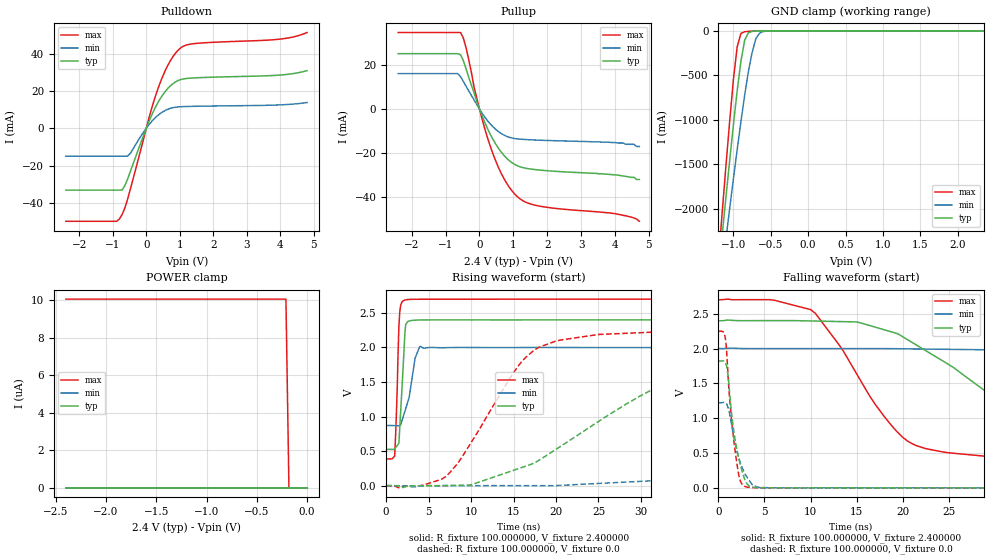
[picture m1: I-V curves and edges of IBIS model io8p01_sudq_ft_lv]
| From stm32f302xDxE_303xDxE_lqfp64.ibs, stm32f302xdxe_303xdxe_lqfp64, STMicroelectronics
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|   Model io8p01_sudq_ft_lv
[Model]  io8p01_sudq_ft_lv
Model_type I/O
Polarity   Non-Inverting
Enable   Active-Low
Vinl =   0.720000V
Vinh =   1.680000V
Vmeas =  1.200000V
Cref =   50.000000pF
Rref =   100.000000M
Vref =   0.0V
C_comp   1.970100pF   1.887900pF   2.069400pF
[Temperature Range]   25.000000   0.125000k   -40.000000
[Pullup Reference]   2.400000V   2.000000V   2.700000V
[Pulldown Reference]   0.0V   0.0V   0.0V
[POWER Clamp Reference]   2.400000V   2.000000V   2.700000V
[GND Clamp Reference]   0.0V   0.0V   0.0V
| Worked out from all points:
|   slope of the pulldown table from 0 to 0.36 V, typ, clamps not added: 25.5 ohm
|   slope of the pullup table from 0 to 0.36 V, typ, clamps not added: 28.4 ohm
|   GND clamp passes 1 mA (typ) near -0.64 V on its own axis
|   rising waveform, R_fixture 100.000000, V_fixture 2.400000: 20-80 % time 499ps typ, 1.06ns min, 336ps max; typ from 0.525 V to 2.4 V
|   rising waveform, R_fixture 100.000000, V_fixture 0.0: 20-80 % time 14.5ns typ, 43.7ns min, 6.87ns max; typ from 0 V to 1.82 V
|   falling waveform, R_fixture 100.000000, V_fixture 2.400000: 20-80 % time 13ns typ, 32.3ns min, 7.05ns max; typ from 2.4 V to 0.525 V
|   falling waveform, R_fixture 100.000000, V_fixture 0.0: 20-80 % time 1.16ns typ, 1.39ns min, 931ps max; typ from 1.82 V to 0 V
[Pulldown]
|Voltage   I(typ)   I(min)   I(max)
-2.4V     -33.16mA   -14.98mA   -49.86mA
-880mV    -33.16mA   -14.98mA   -49.86mA
-800mV    -33.16mA   -14.98mA   -48.55mA
-640mV    -30.75mA   -14.98mA   -42.76mA
-480mV    -23.43mA   -13.57mA   -32.92mA
80mV      3.651mA    1.905mA    5.506mA
400mV     15.37mA    7.665mA    23.73mA
720mV     22.75mA    10.69mA    36.23mA
1.04V     26.18mA    11.57mA    43.27mA
1.52V     27.09mA    11.81mA    45.55mA
4V        28.55mA    12.55mA    47.81mA
4.8V      30.9mA     13.81mA    51.31mA
[Pullup]
|Voltage   I(typ)   I(min)   I(max)
-2.4V     25.21mA    16.13mA    34.79mA
-640mV    25.21mA    16.13mA    34.79mA
-560mV    24.72mA    14.75mA    34.79mA
-400mV    18.51mA    10.48mA    28.09mA
-160mV    7.322mA    4.15mA     10.02mA
80mV      -3.229mA   -1.94mA    -4.736mA
400mV     -13.82mA   -8.081mA   -20.45mA
800mV     -22.31mA   -12.38mA   -33.66mA
1.2V      -26.24mA   -13.65mA   -40.83mA
1.76V     -27.69mA   -14.12mA   -44.07mA
4V        -29.9mA    -15.2mA    -47.5mA
4.72V     -32mA      -17mA      -51mA
[GND_clamp]
|Voltage   I(typ)   I(min)   I(max)
-2.4V     -9.788A    -9.782A    -9.734A
-1.2V     -2.718A    -3.02A     -2.568A
-1.15V    -2.29A     -2.675A    -2.036A
-1.1V     -1.868A    -2.333A    -1.515A
-1.05V    -1.454A    -1.995A    -1.012A
-950mV    -674.5mA   -1.337A    -180.5mA
-900mV    -345.2mA   -1.023A    -29.72mA
-850mV    -106.4mA   -726mA     -10.13mA
-750mV    -6.396mA   -244mA     -4.026mA
-700mV    -2.558mA   -88.61mA   -2.329mA
-600mV    -416uA     -7.739mA   -368uA
2.35V     0A         0A         0A
[POWER_clamp]
|Voltage   I(typ)   I(min)   I(max)
-2.4V     0A         0A         10.06uA
-210mV    0A         0A         10.06uA
-180mV    0A         0A         0A
0V        0A         0A         0A
[Ramp]
| variable   typ   min   max
dV/dt_r  1.09308/14.53591n   0.73368/43.60005n   1.34946/6.86189n
dV/dt_f  1.12469/12.94342n   0.67781/32.23620n   1.38756/7.04174n
R_load = 100.000000
[Rising Waveform]
R_fixture= 100.000000
V_fixture= 2.400000
V_fixture_min= 2.000000
V_fixture_max= 2.700000
|time   V(typ)   V(min)   V(max)
0s        525.2mV    870.3mV    387.4mV
1.001ns   533.4mV    868.6mV    427.9mV
1.301ns   580.2mV    867mV      1.396V
1.502ns   618.9mV    866.4mV    2.308V
1.702ns   1.058V     877.1mV    2.607V
2.202ns   2.2V       1.075V     2.686V
2.703ns   2.383V     1.274V     2.696V
3.403ns   2.395V     1.844V     2.698V
4.004ns   2.398V     2.016V     2.698V
49.85ns   2.4V       2V         2.7V
[Rising Waveform]
R_fixture= 100.000000
V_fixture= 0.0
V_fixture_min= 0.0
V_fixture_max= 0.0
|time   V(typ)   V(min)   V(max)
0s        1.81nV     16.19nV    1.388nV
7.007ns   1.867mV    817.4uV    130.2mV
16.52ns   286.2mV    456uV      1.866V
20.02ns   528mV      1.164mV    2.095V
25.03ns   931.2mV    32.13mV    2.189V
37.04ns   1.629V     132.6mV    2.24V
54.55ns   1.791V     444.2mV    2.251V
84.08ns   1.821V     947.3mV    2.249V
106.1ns   1.822V     1.128V     2.249V
249.2ns   1.822V     1.223V     2.249V
[Falling Waveform]
R_fixture= 100.000000
V_fixture= 2.400000
V_fixture_min= 2.000000
V_fixture_max= 2.700000
|time   V(typ)   V(min)   V(max)
0s        2.4V       2V         2.7V
10.01ns   2.397V     2V         2.56V
15.02ns   2.383V     2V         1.637V
20.02ns   2.171V     1.997V     726.6mV
29.03ns   1.387V     1.983V     453.9mV
37.04ns   789.8mV    1.94V      415.8mV
52.55ns   592.4mV    1.669V     394.5mV
72.57ns   546.2mV    1.209V     388.6mV
99.1ns    528mV      969.1mV    387.4mV
249.2ns   525.2mV    870.3mV    387.4mV
[Falling Waveform]
R_fixture= 100.000000
V_fixture= 0.0
V_fixture_min= 0.0
V_fixture_max= 0.0
|time   V(typ)   V(min)   V(max)
0s        1.822V     1.223V     2.249V
700.7ps   1.802V     1.223V     2.18V
800.8ps   1.785V     1.216V     2.097V
1.001ns   1.655V     1.166V     1.704V
1.201ns   1.378V     1.071V     1.289V
1.902ns   616.6mV    591.6mV    436.6mV
2.302ns   369.3mV    388.2mV    131.7mV
2.903ns   108.1mV    191.2mV    18.1mV
4.705ns   2.197mV    4.103mV    1.139mV
49.85ns   1.81nV     16.19nV    1.388nV
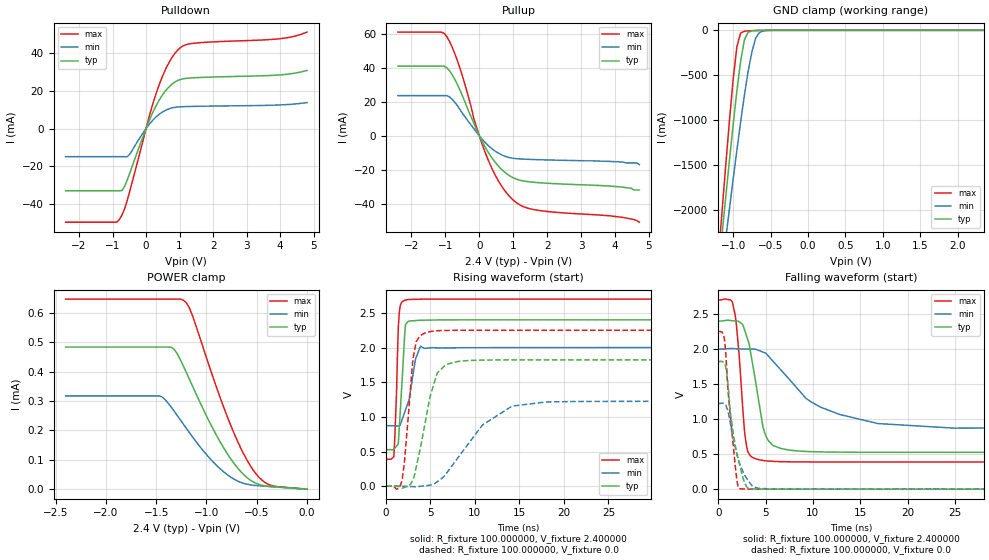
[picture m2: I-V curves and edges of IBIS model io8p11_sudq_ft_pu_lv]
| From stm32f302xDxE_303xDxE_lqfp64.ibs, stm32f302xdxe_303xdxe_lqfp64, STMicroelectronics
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|   Model io8p11_sudq_ft_pu_lv
[Model]  io8p11_sudq_ft_pu_lv
Model_type I/O
Polarity   Non-Inverting
Enable   Active-Low
Vinl =   0.720000V
Vinh =   1.680000V
Vmeas =  1.200000V
Cref =   50.000000pF
Rref =   100.000000M
Vref =   0.0V
C_comp   1.970100pF   1.887900pF   2.069400pF
[Temperature Range]   25.000000   0.125000k   -40.000000
[Pullup Reference]   2.400000V   2.000000V   2.700000V
[Pulldown Reference]   0.0V   0.0V   0.0V
[POWER Clamp Reference]   2.400000V   2.000000V   2.700000V
[GND Clamp Reference]   0.0V   0.0V   0.0V
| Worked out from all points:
|   slope of the pulldown table from 0 to 0.36 V, typ, clamps not added: 25.5 ohm
|   slope of the pullup table from 0 to 0.36 V, typ, clamps not added: 28.4 ohm
|   GND clamp passes 1 mA (typ) near -0.64 V on its own axis
|   rising waveform, R_fixture 100.000000, V_fixture 2.400000: 20-80 % time 508ps typ, 1.05ns min, 337ps max; typ from 0.527 V to 2.4 V
|   rising waveform, R_fixture 100.000000, V_fixture 0.0: 20-80 % time 1.8ns typ, 4.87ns min, 863ps max; typ from 0.001 V to 1.82 V
|   falling waveform, R_fixture 100.000000, V_fixture 2.400000: 20-80 % time 1.39ns typ, 6.08ns min, 775ps max; typ from 2.4 V to 0.527 V
|   falling waveform, R_fixture 100.000000, V_fixture 0.0: 20-80 % time 1.17ns typ, 1.4ns min, 853ps max; typ from 1.82 V to 0.001 V
[Pulldown]
|Voltage   I(typ)   I(min)   I(max)
-2.4V     -33.16mA   -14.98mA   -49.86mA
-880mV    -33.16mA   -14.98mA   -49.86mA
-800mV    -33.16mA   -14.98mA   -48.55mA
-640mV    -30.75mA   -14.98mA   -42.77mA
-480mV    -23.43mA   -13.57mA   -32.92mA
80mV      3.651mA    1.905mA    5.506mA
400mV     15.37mA    7.665mA    23.73mA
720mV     22.75mA    10.69mA    36.23mA
1.04V     26.18mA    11.57mA    43.27mA
1.52V     27.09mA    11.81mA    45.55mA
4V        28.55mA    12.55mA    47.81mA
4.8V      30.9mA     13.81mA    51.31mA
[Pullup]
|Voltage   I(typ)   I(min)   I(max)
-2.4V     41.12mA    23.71mA    61.21mA
-1.12V    41.12mA    23.71mA    61.21mA
-960mV    40.18mA    23.71mA    58.56mA
-800mV    36.01mA    21.55mA    52.29mA
-560mV    26.54mA    15.18mA    39.21mA
-160mV    7.421mA    4.162mA    10.02mA
240mV     -8.977mA   -5.327mA   -13.21mA
640mV     -19.51mA   -11.09mA   -29.16mA
1.04V     -25.15mA   -13.38mA   -38.61mA
1.68V     -27.56mA   -14.07mA   -43.82mA
3.84V     -29.6mA    -15.1mA    -47.2mA
4.72V     -32mA      -17mA      -51mA
[GND_clamp]
|Voltage   I(typ)   I(min)   I(max)
-2.4V     -9.788A    -9.782A    -9.734A
-1.2V     -2.718A    -3.02A     -2.568A
-1.15V    -2.29A     -2.675A    -2.036A
-1.1V     -1.868A    -2.333A    -1.515A
-1.05V    -1.454A    -1.995A    -1.012A
-950mV    -674.5mA   -1.337A    -180.5mA
-900mV    -345.2mA   -1.023A    -29.72mA
-850mV    -106.4mA   -726mA     -10.13mA
-750mV    -6.396mA   -244mA     -4.026mA
-700mV    -2.558mA   -88.61mA   -2.329mA
-600mV    -416uA     -7.739mA   -368uA
2.35V     0A         0A         0A
[POWER_clamp]
|Voltage   I(typ)   I(min)   I(max)
-2.4V     483.8uA    317.4uA    647uA
-1.47V    483.8uA    317.4uA    647uA
-1.32V    475.6uA    265.2uA    647uA
-1.23V    419.7uA    221.6uA    643.3uA
-1.17V    374.8uA    192.7uA    617.6uA
-1.14V    352.1uA    178.7uA    591.9uA
-840mV    147uA      62.15uA    289.6uA
-690mV    72.24uA    27.76uA    162.7uA
-540mV    25.74uA    13.55uA    67.63uA
-450mV    13.38uA    10.75uA    31.36uA
-360mV    9.231uA    8.535uA    12.97uA
0V        0A         0A         0A
[Ramp]
| variable   typ   min   max
dV/dt_r  1.09269/1.79328n   0.73359/4.86832n   1.34926/0.85997n
dV/dt_f  1.12411/1.38607n   0.67669/6.07307n   1.38681/0.77427n
R_load = 100.000000
[Rising Waveform]
R_fixture= 100.000000
V_fixture= 2.400000
V_fixture_min= 2.000000
V_fixture_max= 2.700000
|time   V(typ)   V(min)   V(max)
0s        526.5mV    872.5mV    388.6mV
900.9ps   534.2mV    870.9mV    425.1mV
1.201ns   577.4mV    869.6mV    1.365V
1.401ns   613.7mV    869.2mV    2.295V
1.602ns   1.046V     879.2mV    2.598V
2.202ns   2.333V     1.099V     2.686V
2.603ns   2.381V     1.245V     2.693V
3.303ns   2.389V     1.817V     2.697V
3.904ns   2.394V     2.019V     2.698V
49.85ns   2.4V       2V         2.7V
[Rising Waveform]
R_fixture= 100.000000
V_fixture= 0.0
V_fixture_min= 0.0
V_fixture_max= 0.0
|time   V(typ)   V(min)   V(max)
0s        1.022mV    1.341mV    911uV
1.802ns   -26.21mV   109.9uV    74.5mV
3.103ns   116.7mV    -6.8mV     1.877V
3.403ns   271.6mV    -8.185mV   2.086V
4.505ns   979.1mV    4.99mV     2.215V
5.706ns   1.605V     58.19mV    2.241V
6.707ns   1.752V     167.1mV    2.247V
10.81ns   1.819V     875.7mV    2.25V
14.21ns   1.822V     1.156V     2.25V
49.85ns   1.822V     1.224V     2.25V
[Falling Waveform]
R_fixture= 100.000000
V_fixture= 2.400000
V_fixture_min= 2.000000
V_fixture_max= 2.700000
|time   V(typ)   V(min)   V(max)
0s        2.4V       2V         2.7V
1.502ns   2.403V     2.008V     2.671V
1.902ns   2.401V     2.004V     2.37V
2.903ns   2.224V     2.001V     697.7mV
4.004ns   1.486V     1.995V     432.1mV
5.205ns   712.7mV    1.914V     402.8mV
7.508ns   558.9mV    1.567V     391mV
10.81ns   532.3mV    1.17V      388.6mV
16.82ns   526.7mV    938mV      388.6mV
49.85ns   526.5mV    872.5mV    388.6mV
[Falling Waveform]
R_fixture= 100.000000
V_fixture= 0.0
V_fixture_min= 0.0
V_fixture_max= 0.0
|time   V(typ)   V(min)   V(max)
0s        1.822V     1.224V     2.25V
700.7ps   1.784V     1.216V     2.102V
1.101ns   1.384V     1.072V     1.307V
1.301ns   1.083V     926.1mV    1.012V
1.802ns   627.4mV    595.9mV    327.6mV
2.102ns   434.5mV    435.4mV    35.99mV
2.302ns   325.6mV    349.7mV    5.728mV
3.103ns   17.78mV    137.1mV    2.333mV
4.605ns   2.394mV    9.48mV     1.404mV
49.85ns   1.022mV    1.341mV    911uV
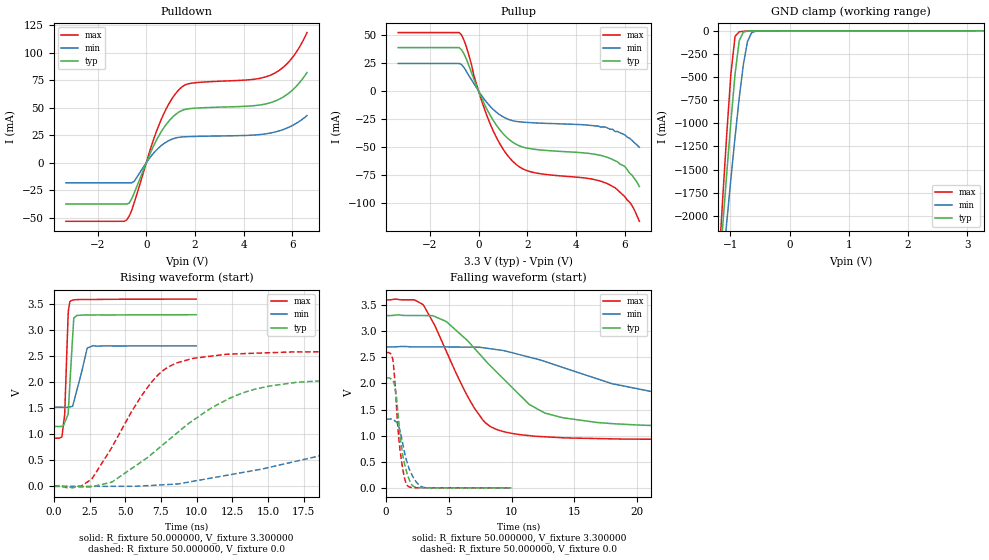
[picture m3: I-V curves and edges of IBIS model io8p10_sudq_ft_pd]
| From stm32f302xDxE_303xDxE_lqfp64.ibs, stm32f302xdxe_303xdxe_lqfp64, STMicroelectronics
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|   Model io8p10_sudq_ft_pd
[Model]  io8p10_sudq_ft_pd
Model_type I/O
Polarity   Non-Inverting
Enable   Active-Low
Vinl =   0.990000V
Vinh =   2.310000V
Vmeas =  1.650000V
Cref =   50.000000pF
Rref =   100.000000M
Vref =   0.0V
C_comp   1.970900pF   1.892300pF   2.063200pF
[Temperature Range]   25.000000   0.125000k   -40.000000
[Pullup Reference]   3.300000V   2.700000V   3.600000V
[Pulldown Reference]   0.0V   0.0V   0.0V
[POWER Clamp Reference]   3.300000V   2.700000V   3.600000V
[GND Clamp Reference]   0.0V   0.0V   0.0V
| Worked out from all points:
|   slope of the pulldown table from 0 to 0.495 V, typ, clamps not added: 20.9 ohm
|   slope of the pullup table from 0 to 0.495 V, typ, clamps not added: 22.2 ohm
|   GND clamp passes 1 mA (typ) near -0.64 V on its own axis
|   rising waveform, R_fixture 50.000000, V_fixture 3.300000: 20-80 % time 274ps typ, 646ps min, 201ps max; typ from 1.15 V to 3.3 V
|   rising waveform, R_fixture 50.000000, V_fixture 0.0: 20-80 % time 6.37ns typ, 15.3ns min, 3.53ns max; typ from 0 V to 2.1 V
|   falling waveform, R_fixture 50.000000, V_fixture 3.300000: 20-80 % time 5.28ns typ, 10.9ns min, 3.27ns max; typ from 3.3 V to 1.15 V
|   falling waveform, R_fixture 50.000000, V_fixture 0.0: 20-80 % time 663ps typ, 882ps min, 541ps max; typ from 2.1 V to 0 V
[Pulldown]
|Voltage   I(typ)   I(min)   I(max)
-3.3V     -37.45mA   -18.2mA    -53.24mA
-800mV    -37.45mA   -18.2mA    -51.9mA
-700mV    -36.7mA    -18.2mA    -48.48mA
-500mV    -27.71mA   -17.01mA   -36.66mA
200mV     10.57mA    6.084mA    14.57mA
500mV     23.91mA    13.38mA    33.24mA
900mV     37.17mA    19.88mA    52.48mA
1.3V      45.55mA    23.01mA    65.5mA
1.8V      49.29mA    23.83mA    72.18mA
5.1V      54.68mA    27.07mA    79.72mA
5.9V      64.2mA     32.82mA    93.01mA
6.6V      82.13mA    42.97mA    118.5mA
[Pullup]
|Voltage   I(typ)   I(min)   I(max)
-3.3V     38.73mA    24.61mA    52.1mA
-800mV    38.73mA    24.61mA    52.1mA
-500mV    28.37mA    17.48mA    39.19mA
0V        0A         0A         0A
500mV     -22.5mA    -14.16mA   -30.52mA
900mV     -35.28mA   -21.55mA   -48mA
1.4V      -45.55mA   -26.41mA   -62.54mA
2.2V      -51.57mA   -28.22mA   -72.25mA
5.3V      -59.1mA    -33mA      -82.6mA
6V        -67mA      -39mA      -94mA
6.2V      -73mA      -42mA      -99mA
6.6V      -85mA      -50mA      -116mA
[GND_clamp]
|Voltage   I(typ)   I(min)   I(max)
-3.3V     -9.525A    -9.501A    -9.513A
-1.2V     -2.719A    -3.023A    -2.568A
-1.13V    -2.122A    -2.541A    -1.826A
-1.06V    -1.537A    -2.065A    -1.111A
-990mV    -975.7mA   -1.599A    -462mA
-920mV    -467.5mA   -1.149A    -59.02mA
-850mV    -106.6mA   -727.3mA   -10.13mA
-780mV    -13.08mA   -365.4mA   -5.271mA
-710mV    -3.06mA    -114.8mA   -2.651mA
-640mV    -957.2uA   -20.17mA   -921.6uA
-570mV    -212.9uA   -3.969mA   -172uA
3.28V     83.81uA    63.75uA    93.54uA
[POWER_clamp]
|Voltage   I(typ)   I(min)   I(max)
-3.28V    0A         0A         0A
0V        0A         0A         0A
[Ramp]
| variable   typ   min   max
dV/dt_r  1.26150/6.36494n   0.77862/15.28889n   1.55382/3.52251n
dV/dt_f  1.28916/5.27830n   0.70008/10.90013n   1.60430/3.26463n
R_load = 50.000000
[Rising Waveform]
R_fixture= 50.000000
V_fixture= 3.300000
V_fixture_min= 2.700000
V_fixture_max= 3.600000
|time   V(typ)   V(min)   V(max)
0s        1.15V      1.521V     925.1mV
560.6ps   1.152V     1.52V      947.6mV
760.8ps   1.229V     1.519V     1.381V
1.001ns   1.382V     1.522V     3.286V
1.141ns   2.049V     1.528V     3.554V
1.401ns   3.239V     1.626V     3.584V
1.622ns   3.287V     1.856V     3.589V
2.342ns   3.294V     2.658V     3.591V
2.743ns   3.295V     2.703V     3.592V
9.97ns    3.299V     2.699V     3.599V
[Rising Waveform]
R_fixture= 50.000000
V_fixture= 0.0
V_fixture_min= 0.0
V_fixture_max= 0.0
|time   V(typ)   V(min)   V(max)
0s        -32.87uV   -23.39uV   -20.28uV
2.603ns   -244.8uV   -5.328mV   130.3mV
4.104ns   87.71mV    -415.2uV   769.1mV
7.007ns   653.5mV    19.49mV    2.054V
8.008ns   882.6mV    34.81mV    2.294V
9.81ns    1.278V     99.57mV    2.462V
13.01ns   1.773V     255.5mV    2.548V
17.02ns   1.999V     484.8mV    2.584V
32.23ns   2.1V       1.162V     2.591V
49.85ns   2.103V     1.315V     2.59V
[Falling Waveform]
R_fixture= 50.000000
V_fixture= 3.300000
V_fixture_min= 2.700000
V_fixture_max= 3.600000
|time   V(typ)   V(min)   V(max)
0s        3.299V     2.699V     3.599V
2.903ns   3.3V       2.699V     3.516V
4.805ns   3.183V     2.698V     2.61V
7.007ns   2.681V     2.694V     1.537V
8.208ns   2.36V      2.668V     1.191V
9.71ns    2.002V     2.607V     1.058V
12.61ns   1.436V     2.423V     978.4mV
16.82ns   1.252V     2.088V     944.2mV
23.52ns   1.179V     1.733V     929.4mV
49.85ns   1.15V      1.521V     925.1mV
[Falling Waveform]
R_fixture= 50.000000
V_fixture= 0.0
V_fixture_min= 0.0
V_fixture_max= 0.0
|time   V(typ)   V(min)   V(max)
0s        2.103V     1.315V     2.59V
520.5ps   2.061V     1.313V     2.467V
760.8ps   1.842V     1.271V     1.802V
981ps     1.331V     1.18V      1.013V
1.101ns   1.021V     1.092V     734.9mV
1.441ns   483.4mV    706.1mV    213.2mV
1.742ns   223.1mV    432.6mV    31.37mV
2.162ns   30.01mV    201.7mV    5.073mV
3.003ns   1.727mV    9.018mV    1.539mV
9.97ns    -32.87uV   -23.39uV   -20.28uV
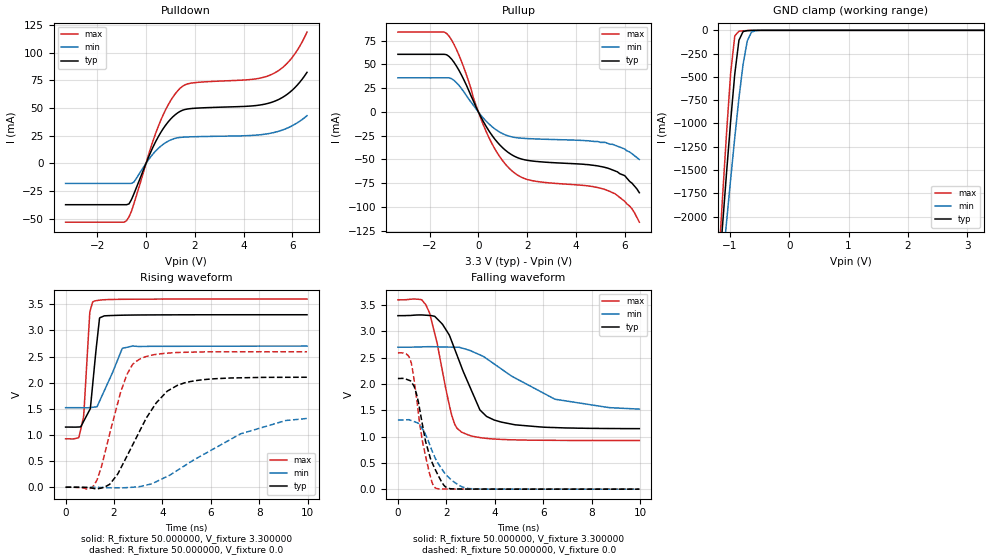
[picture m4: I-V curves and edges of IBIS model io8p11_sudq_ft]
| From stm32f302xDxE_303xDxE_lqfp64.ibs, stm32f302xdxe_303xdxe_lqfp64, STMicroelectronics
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|   Model io8p11_sudq_ft
[Model]  io8p11_sudq_ft
Model_type I/O
Polarity   Non-Inverting
Enable   Active-Low
Vinl =   0.990000V
Vinh =   2.310000V
Vmeas =  1.650000V
Cref =   30.000000pF
Rref =   100.000000M
Vref =   0.0V
C_comp   1.970900pF   1.892300pF   2.063200pF
[Temperature Range]   25.000000   0.125000k   -40.000000
[Pullup Reference]   3.300000V   2.700000V   3.600000V
[Pulldown Reference]   0.0V   0.0V   0.0V
[POWER Clamp Reference]   3.300000V   2.700000V   3.600000V
[GND Clamp Reference]   0.0V   0.0V   0.0V
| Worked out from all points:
|   slope of the pulldown table from 0 to 0.495 V, typ, clamps not added: 20.9 ohm
|   slope of the pullup table from 0 to 0.495 V, typ, clamps not added: 22.2 ohm
|   GND clamp passes 1 mA (typ) near -0.64 V on its own axis
|   rising waveform, R_fixture 50.000000, V_fixture 3.300000: 20-80 % time 277ps typ, 662ps min, 203ps max; typ from 1.15 V to 3.3 V
|   rising waveform, R_fixture 50.000000, V_fixture 0.0: 20-80 % time 1.54ns typ, 3.04ns min, 916ps max; typ from 0 V to 2.1 V
|   falling waveform, R_fixture 50.000000, V_fixture 3.300000: 20-80 % time 1.14ns typ, 2.57ns min, 732ps max; typ from 3.3 V to 1.15 V
|   falling waveform, R_fixture 50.000000, V_fixture 0.0: 20-80 % time 661ps typ, 876ps min, 528ps max; typ from 2.1 V to 0 V
[Pulldown]
|Voltage   I(typ)   I(min)   I(max)
-3.3V     -37.45mA   -18.2mA    -53.24mA
-800mV    -37.45mA   -18.2mA    -51.9mA
-700mV    -36.7mA    -18.2mA    -48.48mA
-500mV    -27.71mA   -17.01mA   -36.66mA
200mV     10.57mA    6.084mA    14.57mA
500mV     23.91mA    13.38mA    33.24mA
900mV     37.17mA    19.88mA    52.48mA
1.3V      45.55mA    23.01mA    65.5mA
1.8V      49.29mA    23.83mA    72.18mA
5.1V      54.68mA    27.07mA    79.72mA
5.9V      64.2mA     32.82mA    93.01mA
6.6V      82.13mA    42.97mA    118.4mA
[Pullup]
|Voltage   I(typ)   I(min)   I(max)
-3.3V     60.69mA    35.92mA    84.08mA
-1.4V     60.69mA    35.92mA    84.08mA
-1.2V     58.36mA    35.92mA    79.66mA
-700mV    39.17mA    24.85mA    53.68mA
0V        90fA       16pA       0A
400mV     -18.61mA   -11.78mA   -25.23mA
900mV     -35.28mA   -21.55mA   -48mA
1.5V      -46.91mA   -26.86mA   -64.58mA
2.2V      -51.57mA   -28.22mA   -72.25mA
5.4V      -60mA      -34mA      -83.7mA
6.2V      -73mA      -42mA      -99mA
6.6V      -85mA      -50mA      -116mA
[GND_clamp]
|Voltage   I(typ)   I(min)   I(max)
-3.3V     -9.525A    -9.501A    -9.513A
-1.2V     -2.719A    -3.023A    -2.568A
-1.13V    -2.122A    -2.541A    -1.826A
-1.06V    -1.537A    -2.065A    -1.111A
-990mV    -975.7mA   -1.599A    -462mA
-920mV    -467.4mA   -1.149A    -59mA
-850mV    -106.6mA   -727.3mA   -10.11mA
-780mV    -13.06mA   -365.4mA   -5.254mA
-710mV    -3.045mA   -114.8mA   -2.635mA
-640mV    -943.2uA   -20.16mA   -905.7uA
-570mV    -199.4uA   -3.959mA   -156.8uA
3.28V     0A         0A         0A
[POWER_clamp]
|Voltage   I(typ)   I(min)   I(max)
-3.28V    0A         0A         0A
0V        0A         0A         0A
[Ramp]
| variable   typ   min   max
dV/dt_r  1.26204/1.54199n   0.74154/3.07545n   1.55460/0.91488n
dV/dt_f  1.28820/1.14146n   0.68808/2.59071n   1.60477/0.73113n
R_load = 50.000000
[Rising Waveform]
R_fixture= 50.000000
V_fixture= 3.300000
V_fixture_min= 2.700000
V_fixture_max= 3.600000
|time   V(typ)   V(min)   V(max)
0s        1.151V     1.522V     925.6mV
540.5ps   1.153V     1.522V     946.3mV
740.7ps   1.257V     1.521V     1.344V
1.001ns   1.485V     1.525V     3.355V
1.121ns   1.978V     1.53V      3.548V
1.401ns   3.233V     1.646V     3.579V
1.602ns   3.278V     1.85V      3.587V
2.342ns   3.291V     2.657V     3.595V
2.763ns   3.294V     2.701V     3.596V
9.97ns    3.3V       2.7V       3.6V
[Rising Waveform]
R_fixture= 50.000000
V_fixture= 0.0
V_fixture_min= 0.0
V_fixture_max= 0.0
|time   V(typ)   V(min)   V(max)
0s        -11.47uV   -27.38uV   -6.456uV
1.181ns   -24.48mV   -1.04mV    43.67mV
1.481ns   -14.38mV   -4.331mV   396.7mV
1.822ns   56.8mV     -9.555mV   1.023V
2.523ns   585.5mV    -6.9mV     2.148V
3.043ns   1.06V      10.88mV    2.446V
3.744ns   1.615V     106.8mV    2.543V
4.905ns   1.996V     408.5mV    2.581V
7.227ns   2.094V     1.022V     2.592V
9.97ns    2.104V     1.316V     2.592V
[Falling Waveform]
R_fixture= 50.000000
V_fixture= 3.300000
V_fixture_min= 2.700000
V_fixture_max= 3.600000
|time   V(typ)   V(min)   V(max)
0s        3.3V       2.7V       3.6V
961ps     3.314V     2.705V     3.605V
1.161ns   3.308V     2.709V     3.497V
1.622ns   3.239V     2.707V     2.77V
2.222ns   2.811V     2.701V     1.406V
2.623ns   2.327V     2.687V     1.086V
3.383ns   1.509V     2.554V     981.2mV
3.984ns   1.313V     2.379V     953.7mV
6.486ns   1.171V     1.71V      928.4mV
9.97ns    1.151V     1.522V     925.6mV
[Falling Waveform]
R_fixture= 50.000000
V_fixture= 0.0
V_fixture_min= 0.0
V_fixture_max= 0.0
|time   V(typ)   V(min)   V(max)
0s        2.104V     1.316V     2.592V
340.3ps   2.092V     1.32V      2.572V
560.6ps   2.034V     1.303V     2.384V
760.8ps   1.821V     1.269V     1.763V
1.021ns   1.205V     1.141V     888.3mV
1.401ns   518.9mV    738.5mV    138.8mV
1.582ns   336.1mV    547.5mV    14.88mV
2.002ns   33.13mV    264.1mV    2.736mV
2.863ns   1.972mV    16.69mV    1.045mV
9.97ns    -11.47uV   -27.38uV   -6.456uV
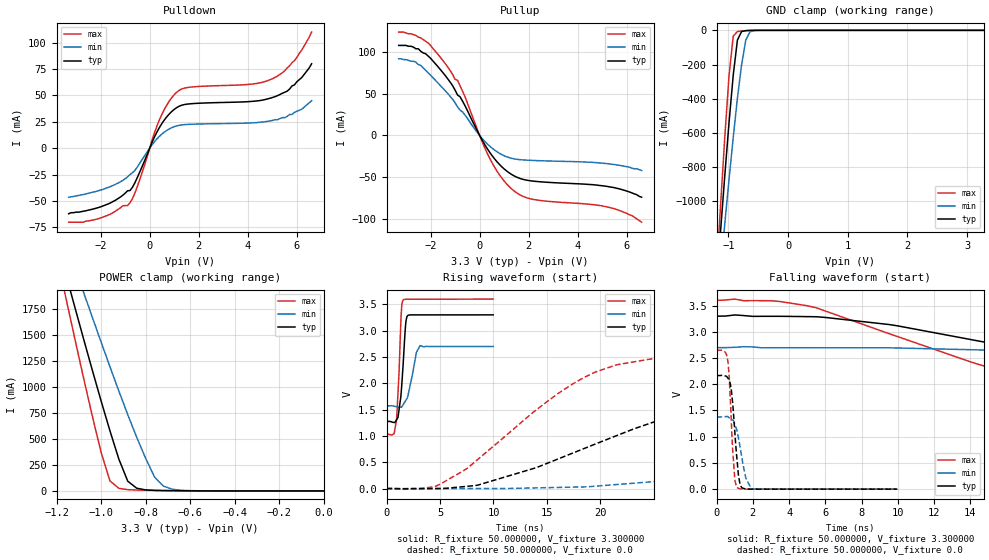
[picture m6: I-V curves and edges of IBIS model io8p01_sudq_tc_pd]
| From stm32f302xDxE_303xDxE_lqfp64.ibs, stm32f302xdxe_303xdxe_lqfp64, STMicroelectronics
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|   Model io8p01_sudq_tc_pd
[Model]  io8p01_sudq_tc_pd
Model_type I/O
Polarity   Non-Inverting
Enable   Active-Low
Vinl =   0.990000V
Vinh =   2.310000V
Vmeas =  1.650000V
Cref =   50.000000pF
Rref =   100.000000M
Vref =   0.0V
C_comp   1.329900pF   1.255600pF   1.431200pF
[Temperature Range]   25.000000   0.125000k   -40.000000
[Pullup Reference]   3.300000V   2.700000V   3.600000V
[Pulldown Reference]   0.0V   0.0V   0.0V
[POWER Clamp Reference]   3.300000V   2.700000V   3.600000V
[GND Clamp Reference]   0.0V   0.0V   0.0V
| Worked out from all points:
|   slope of the pulldown table from 0 to 0.495 V, typ, clamps not added: 21.3 ohm
|   slope of the pullup table from 0 to 0.495 V, typ, clamps not added: 20.9 ohm
|   GND clamp passes 1 mA (typ) near -0.66 V on its own axis
|   POWER clamp passes 1 mA (typ) near -0.60 V on its own axis
|   rising waveform, R_fixture 50.000000, V_fixture 3.300000: 20-80 % time 415ps typ, 658ps min, 323ps max; typ from 1.27 V to 3.3 V
|   rising waveform, R_fixture 50.000000, V_fixture 0.0: 20-80 % time 18.4ns typ, 45.6ns min, 10.2ns max; typ from 0 V to 2.17 V
|   falling waveform, R_fixture 50.000000, V_fixture 3.300000: 20-80 % time 25.7ns typ, 44.2ns min, 16.3ns max; typ from 3.3 V to 1.27 V
|   falling waveform, R_fixture 50.000000, V_fixture 0.0: 20-80 % time 301ps typ, 443ps min, 234ps max; typ from 2.17 V to 0 V
[Pulldown]
|Voltage   I(typ)   I(min)   I(max)
-3.3V     -62mA      -46.4mA    -70mA
-2.1V     -56.2mA    -40.3mA    -66.8mA
-800mV    -40.04mA   -24.9mA    -51.58mA
-500mV    -27.57mA   -17.6mA    -36.07mA
400mV     19.71mA    11.36mA    27.01mA
700mV     29.83mA    16.93mA    40.97mA
1.1V      38.46mA    21.2mA     53.02mA
1.6V      41.98mA    22.62mA    57.7mA
4.1V      44.26mA    24mA       60.59mA
5V        48mA       26.3mA     65.8mA
5.9V      60mA       34mA       83mA
6.6V      80mA       45mA       110mA
[Pullup]
|Voltage   I(typ)   I(min)   I(max)
-3.3V     108mA      92mA       124mA
-2.6V     104mA      88mA       120mA
-2.2V     98mA       78.2mA     113mA
-1.4V     71.8mA     53.6mA     86.1mA
-900mV    48.51mA    34.23mA    66.14mA
-700mV    41.33mA    28.36mA    53.31mA
400mV     -19.77mA   -12.52mA   -26.8mA
900mV     -37.48mA   -22.89mA   -50.99mA
1.4V      -48.39mA   -28.06mA   -66.43mA
2.2V      -54.79mA   -29.98mA   -76.75mA
5.3V      -61.7mA    -34.2mA    -86.4mA
6.6V      -74mA      -42mA      -104mA
[GND_clamp]
|Voltage   I(typ)   I(min)   I(max)
-3.3V     -9.739A    -9.975A    -9.587A
-1.2V     -1.489A    -1.65A     -1.416A
-1.13V    -1.162A    -1.385A    -1.009A
-1.06V    -842.3mA   -1.125A    -616.9mA
-990mV    -537.1mA   -870.2mA   -263mA
-920mV    -262.5mA   -625.3mA   -33.98mA
-850mV    -56.96mA   -397.5mA   -7.097mA
-780mV    -7.026mA   -202.3mA   -3.727mA
-710mV    -1.792mA   -58.24mA   -1.753mA
-640mV    -564.1uA   -8.795mA   -558.4uA
-570mV    -123.3uA   -1.303mA   -102.2uA
3.28V     84.11uA    64.12uA    93.81uA
[POWER_clamp]
|Voltage   I(typ)   I(min)   I(max)
-3.28V    9.897A     9.838A     9.594A
-1.16V    2.103A     2.419A     1.88A
-1.12V    1.788A     2.17A      1.488A
-1.08V    1.476A     1.923A     1.102A
-1V       868.1mA    1.435A     373.1mA
-960mV    578.2mA    1.196A     96.06mA
-880mV    93.24mA    734.1mA    12.01mA
-840mV    26.3mA     517.4mA    8.56mA
-760mV    5.106mA    134mA      5.119mA
-720mV    3.355mA    46.34mA    3.808mA
-600mV    1.005mA    2.564mA    1.072mA
0V        0A         0A         0A
[Ramp]
| variable   typ   min   max
dV/dt_r  1.29954/18.39351n   0.82614/45.51681n   1.58820/10.14227n
dV/dt_f  1.21518/25.72183n   0.67764/44.13554n   1.54236/16.30468n
R_load = 50.000000
[Rising Waveform]
R_fixture= 50.000000
V_fixture= 3.300000
V_fixture_min= 2.700000
V_fixture_max= 3.600000
|time   V(typ)   V(min)   V(max)
0s        1.274V     1.569V     1.029V
700.7ps   1.255V     1.565V     1.041V
940.9ps   1.307V     1.552V     1.305V
1.161ns   1.482V     1.546V     2.165V
1.361ns   1.803V     1.544V     3.273V
1.562ns   2.388V     1.596V     3.58V
1.902ns   3.262V     1.706V     3.596V
2.783ns   3.299V     2.577V     3.596V
3.143ns   3.299V     2.715V     3.596V
9.97ns    3.299V     2.699V     3.599V
[Rising Waveform]
R_fixture= 50.000000
V_fixture= 0.0
V_fixture_min= 0.0
V_fixture_max= 0.0
|time   V(typ)   V(min)   V(max)
0s        1.008nV    9.499nV    1.541nV
5.005ns   469.6uV    -186.6uV   81.63mV
8.509ns   63.58mV    54.46uV    549.6mV
15.52ns   519.7mV    19.2mV     1.727V
19.52ns   845.6mV    44.83mV    2.213V
25.53ns   1.301V     140.5mV    2.489V
33.53ns   1.761V     268mV      2.592V
47.55ns   2.061V     575.2mV    2.636V
88.59ns   2.164V     1.19V      2.647V
249.2ns   2.166V     1.377V     2.647V
[Falling Waveform]
R_fixture= 50.000000
V_fixture= 3.300000
V_fixture_min= 2.700000
V_fixture_max= 3.600000
|time   V(typ)   V(min)   V(max)
0s        3.299V     2.699V     3.599V
3.003ns   3.296V     2.697V     3.593V
5.506ns   3.288V     2.697V     3.458V
16.52ns   2.696V     2.639V     2.169V
25.53ns   2.175V     2.465V     1.5V
32.03ns   1.901V     2.339V     1.242V
40.04ns   1.651V     2.186V     1.112V
55.06ns   1.406V     1.952V     1.052V
106.1ns   1.278V     1.621V     1.028V
249.2ns   1.274V     1.569V     1.029V
[Falling Waveform]
R_fixture= 50.000000
V_fixture= 0.0
V_fixture_min= 0.0
V_fixture_max= 0.0
|time   V(typ)   V(min)   V(max)
0s        2.166V     1.377V     2.647V
620.6ps   2.12V      1.381V     2.447V
700.7ps   2.074V     1.361V     2.127V
820.8ps   1.876V     1.333V     1.253V
1.001ns   1.128V     1.24V      219.2mV
1.161ns   443.1mV    1.057V     24.06mV
1.381ns   32.52mV    631.5mV    2.806mV
1.622ns   5.152mV    203.7mV    218.6uV
1.942ns   354.5uV    3.638mV    33.86uV
9.97ns    1.008nV    9.499nV    1.541nV
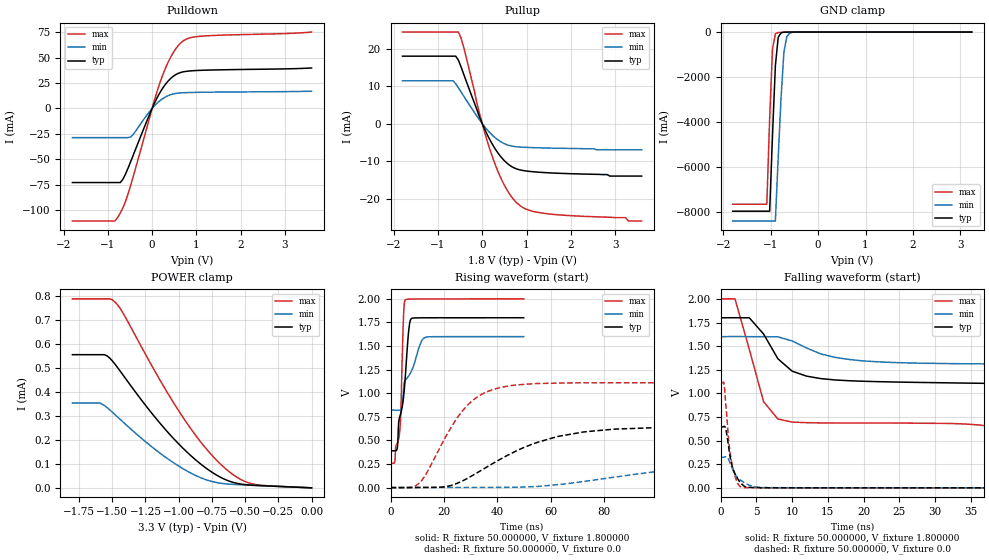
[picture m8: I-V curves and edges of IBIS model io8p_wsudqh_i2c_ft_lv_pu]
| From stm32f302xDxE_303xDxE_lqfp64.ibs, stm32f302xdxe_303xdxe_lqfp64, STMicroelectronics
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|   Model io8p_wsudqh_i2c_ft_lv_pu
[Model]  io8p_wsudqh_i2c_ft_lv_pu
Model_type I/O
Polarity   Non-Inverting
Enable   Active-Low
Vinl =   0.540000V
Vinh =   1.260000V
Vmeas =  0.900000V
Cref =   40.000000pF
Rref =   100.000000M
Vref =   0.0V
C_comp   0.0F   0.0F   0.0F
[Temperature Range]   25.000000   0.140000k   -40.000000
[Pullup Reference]   1.800000V   1.600000V   2.000000V
[Pulldown Reference]   0.0V   0.0V   0.0V
[POWER Clamp Reference]   3.300000V   2.700000V   3.600000V
[GND Clamp Reference]   0.0V   0.0V   0.0V
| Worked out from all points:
|   slope of the pulldown table from 0 to 0.27 V, typ, clamps not added: 12.4 ohm
|   slope of the pullup table from 0 to 0.27 V, typ, clamps not added: 42.7 ohm
|   GND clamp passes 1 mA (typ) near -0.61 V on its own axis
|   rising waveform, R_fixture 50.000000, V_fixture 1.800000: 20-80 % time 3.36ns typ, 5.5ns min, 1.19ns max; typ from 0.39 V to 1.8 V
|   rising waveform, R_fixture 50.000000, V_fixture 0.0: 20-80 % time 28.6ns typ, 60.1ns min, 14.6ns max; typ from 0 V to 0.644 V
|   falling waveform, R_fixture 50.000000, V_fixture 1.800000: 20-80 % time 95.3ns typ, 220ns min, 38.6ns max; typ from 1.8 V to 0.39 V
|   falling waveform, R_fixture 50.000000, V_fixture 0.0: 20-80 % time 1.18ns typ, 1.77ns min, 976ps max; typ from 0.644 V to 0 V
[Pulldown]
|Voltage   I(typ)   I(min)   I(max)
-1.8V     -72.82mA   -28.67mA   -110.6mA
-840mV    -72.82mA   -28.67mA   -110.6mA
-780mV    -72.82mA   -28.67mA   -107.2mA
-660mV    -69.63mA   -28.67mA   -97.65mA
-480mV    -51.79mA   -27.98mA   -74.89mA
0V        0A         0A         0A
240mV     19.98mA    9.621mA    32.82mA
420mV     29.47mA    13.52mA    50.45mA
660mV     35.49mA    15.27mA    64.82mA
840mV     36.76mA    15.6mA     69.15mA
1.14V     37.47mA    15.86mA    71.05mA
3.6V      39.71mA    16.9mA     75.01mA
[Pullup]
|Voltage   I(typ)   I(min)   I(max)
-1.8V     18.02mA    11.44mA    24.46mA
-660mV    18.02mA    11.44mA    24.46mA
-540mV    16.98mA    9.606mA    24.46mA
-420mV    13.24mA    7.383mA    20.45mA
-60mV     1.723mA    986.9uA    2.671mA
240mV     -5.743mA   -3.225mA   -9.221mA
540mV     -10.36mA   -5.558mA   -17.32mA
840mV     -12.32mA   -6.245mA   -21.78mA
1.44V     -13.09mA   -6.504mA   -24.02mA
3.24V     -14mA      -7mA       -25.1mA
3.3V      -14mA      -7mA       -26mA
3.6V      -14mA      -7mA       -26mA
[GND_clamp]
|Voltage   I(typ)   I(min)   I(max)
-1.8V     -7.944A    -8.38A     -7.635A
-1.08V    -7.944A    -8.38A     -7.635A
-1.02V    -7.944A    -8.38A     -3.818A
-960mV    -4.573A    -8.38A     -759.3mA
-900mV    -1.502A    -8.38A     -75.03mA
-840mV    -238mA     -5.574A    -20.4mA
-780mV    -36.12mA   -2.918A    -12.65mA
-720mV    -7.999mA   -894.2mA   -8.064mA
-660mV    -2.38mA    -209.5mA   -4.357mA
-600mV    -722.7uA   -49.62mA   -1.754mA
-420mV    -7.04uA    -712.1uA   -10.35uA
3.24V     0A         5.34nA     0A
[POWER_clamp]
|Voltage   I(typ)   I(min)   I(max)
-1.8V     555.9uA    354.7uA    788.9uA
-1.6V     555.9uA    354.7uA    788.9uA
-1.56V    555.9uA    343.9uA    788.9uA
-1.5V     530.3uA    316uA      785.2uA
-1.46V    502uA      295.7uA    763.9uA
-1.18V    296uA      161.6uA    487.8uA
-960mV    161.3uA    77.45uA    287.9uA
-780mV    76.72uA    31.26uA    155uA
-620mV    28.1uA     15.52uA    67.34uA
-520mV    14.79uA    12.29uA    31.41uA
-440mV    10.88uA    10.3uA     15.86uA
0V        0A         6.245nA    0A
[Ramp]
| variable   typ   min   max
dV/dt_r  0.38619/28.58175n   0.19348/59.51081n   0.66637/14.53616n
dV/dt_f  0.84295/94.92194n   0.39559/0.18877u   1.04499/38.32453n
R_load = 50.000000
[Rising Waveform]
R_fixture= 50.000000
V_fixture= 1.800000
V_fixture_min= 1.600000
V_fixture_max= 2.000000
|time   V(typ)   V(min)   V(max)
0s        390.4mV    821.8mV    258.3mV
1.502ns   389.4mV    820.6mV    267.6mV
2.402ns   406.7mV    819.2mV    463.9mV
3.504ns   756.4mV    821.4mV    618.7mV
4.805ns   946mV      1.023V     1.784V
5.506ns   1.171V     1.139V     1.988V
6.807ns   1.668V     1.183V     1.997V
8.008ns   1.794V     1.247V     1.998V
13.01ns   1.8V       1.592V     1.999V
49.85ns   1.8V       1.6V       2V
[Rising Waveform]
R_fixture= 50.000000
V_fixture= 0.0
V_fixture_min= 0.0
V_fixture_max= 0.0
|time   V(typ)   V(min)   V(max)
0s        348.6uV    506.4uV    288.5uV
11.41ns   1.768mV    440.9uV    64.49mV
24.72ns   42.73mV    1.727mV    730.6mV
32.33ns   155.7mV    1.807mV    957.7mV
41.84ns   312.6mV    2.224mV    1.066V
55.16ns   480.9mV    12.15mV    1.103V
83.68ns   619.2mV    110.1mV    1.111V
131.2ns   643.8mV    257.4mV    1.111V
182.6ns   644mV      310.8mV    1.111V
947.1ns   644mV      324.1mV    1.111V
[Falling Waveform]
R_fixture= 50.000000
V_fixture= 1.800000
V_fixture_min= 1.600000
V_fixture_max= 2.000000
|time   V(typ)   V(min)   V(max)
0s        1.8V       1.6V       2V
2.002ns   1.801V     1.602V     2V
6.006ns   1.628V     1.6V       912.2mV
8.008ns   1.366V     1.598V     728.9mV
22.02ns   1.124V     1.334V     686.3mV
80.08ns   945.3mV    1.303V     293.5mV
116.1ns   544.6mV    1.296V     267.1mV
168.2ns   421.2mV    1.199V     259.7mV
340.3ns   391.1mV    851.6mV    258.3mV
997ns     390.4mV    821.8mV    258.3mV
[Falling Waveform]
R_fixture= 50.000000
V_fixture= 0.0
V_fixture_min= 0.0
V_fixture_max= 0.0
|time   V(typ)   V(min)   V(max)
0s        644mV      324.1mV    1.111V
500.5ps   652mV      325.5mV    1.087V
700.7ps   625.3mV    329.1mV    890.1mV
1.101ns   439.9mV    300.2mV    514.7mV
1.301ns   336.8mV    266mV      380.5mV
1.602ns   230.3mV    209.2mV    248.5mV
2.302ns   105.2mV    115.1mV    61.81mV
2.903ns   44.3mV     75.6mV     7.751mV
5.906ns   1.719mV    3.177mV    1.108mV
49.85ns   348.6uV    506.4uV    288.5uV
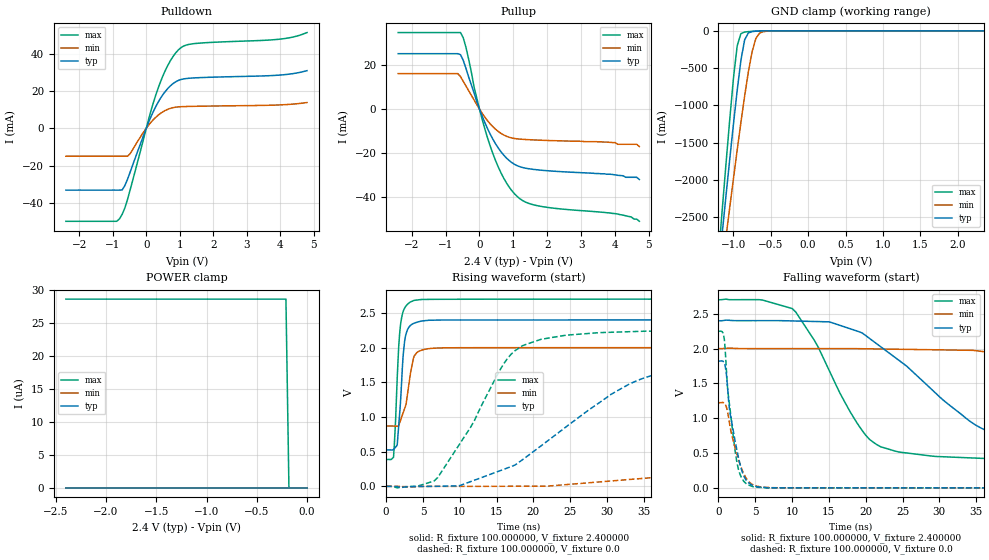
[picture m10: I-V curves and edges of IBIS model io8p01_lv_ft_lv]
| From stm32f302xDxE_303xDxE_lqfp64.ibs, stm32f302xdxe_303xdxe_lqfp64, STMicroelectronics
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|   Model io8p01_lv_ft_lv
[Model]  io8p01_lv_ft_lv
Model_type I/O
Polarity   Non-Inverting
Enable   Active-Low
Vinl =   0.720000V
Vinh =   1.680000V
Vmeas =  1.200000V
Cref =   50.000000pF
Rref =   100.000000M
Vref =   0.0V
C_comp   5.024800pF   4.846300pF   5.260300pF
[Temperature Range]   25.000000   0.125000k   -40.000000
[Pullup Reference]   2.400000V   2.000000V   2.700000V
[Pulldown Reference]   0.0V   0.0V   0.0V
[POWER Clamp Reference]   2.400000V   2.000000V   2.700000V
[GND Clamp Reference]   0.0V   0.0V   0.0V
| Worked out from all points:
|   slope of the pulldown table from 0 to 0.36 V, typ, clamps not added: 25.5 ohm
|   slope of the pullup table from 0 to 0.36 V, typ, clamps not added: 28.4 ohm
|   GND clamp passes 1 mA (typ) near -0.60 V on its own axis
|   rising waveform, R_fixture 100.000000, V_fixture 2.400000: 20-80 % time 715ps typ, 1.15ns min, 633ps max; typ from 0.525 V to 2.4 V
|   rising waveform, R_fixture 100.000000, V_fixture 0.0: 20-80 % time 14.5ns typ, 42.7ns min, 7.19ns max; typ from 0 V to 1.82 V
|   falling waveform, R_fixture 100.000000, V_fixture 2.400000: 20-80 % time 12.9ns typ, 32.5ns min, 7.06ns max; typ from 2.4 V to 0.525 V
|   falling waveform, R_fixture 100.000000, V_fixture 0.0: 20-80 % time 1.65ns typ, 1.85ns min, 1.36ns max; typ from 1.82 V to 0 V
[Pulldown]
|Voltage   I(typ)   I(min)   I(max)
-2.4V     -33.16mA   -14.98mA   -49.86mA
-880mV    -33.16mA   -14.98mA   -49.86mA
-800mV    -33.16mA   -14.98mA   -48.55mA
-640mV    -30.75mA   -14.98mA   -42.77mA
-480mV    -23.43mA   -13.57mA   -32.92mA
80mV      3.651mA    1.905mA    5.506mA
400mV     15.37mA    7.665mA    23.73mA
720mV     22.75mA    10.69mA    36.23mA
1.04V     26.18mA    11.57mA    43.27mA
1.52V     27.09mA    11.81mA    45.55mA
4V        28.55mA    12.55mA    47.81mA
4.8V      30.9mA     13.81mA    51.31mA
[Pullup]
|Voltage   I(typ)   I(min)   I(max)
-2.4V     25.19mA    16.13mA    34.78mA
-640mV    25.19mA    16.13mA    34.78mA
-560mV    24.71mA    14.75mA    34.78mA
-400mV    18.51mA    10.48mA    28.1mA
-160mV    7.327mA    4.151mA    10.02mA
80mV      -3.229mA   -1.94mA    -4.736mA
400mV     -13.82mA   -8.08mA    -20.45mA
800mV     -22.31mA   -12.38mA   -33.66mA
1.2V      -26.24mA   -13.65mA   -40.82mA
1.76V     -27.69mA   -14.12mA   -44.06mA
4V        -29.9mA    -15.2mA    -47.5mA
4.72V     -32mA      -17mA      -51mA
[GND_clamp]
|Voltage   I(typ)   I(min)   I(max)
-2.4V     -9.914A    -9.862A    -9.419A
-1.2V     -3.21A     -3.567A    -3.02A
-1.15V    -2.709A    -3.165A    -2.399A
-1.1V     -2.213A    -2.766A    -1.788A
-1.05V    -1.726A    -2.371A    -1.195A
-950mV    -800.5mA   -1.599A    -202.1mA
-900mV    -394.9mA   -1.228A    -38.17mA
-850mV    -120.2mA   -874.5mA   -15.91mA
-750mV    -9.807mA   -279.4mA   -7.273mA
-700mV    -4.736mA   -102mA     -4.51mA
-600mV    -1.032mA   -11.09mA   -922.6uA
2.35V     0A         0A         0A
[POWER_clamp]
|Voltage   I(typ)   I(min)   I(max)
-2.4V     0A         0A         28.66uA
-210mV    0A         0A         28.66uA
-180mV    0A         0A         0A
0V        0A         0A         0A
[Ramp]
| variable   typ   min   max
dV/dt_r  1.09302/14.45172n   0.73368/42.63681n   1.34958/7.17505n
dV/dt_f  1.12477/12.89960n   0.67753/32.48019n   1.38751/7.04826n
R_load = 100.000000
[Rising Waveform]
R_fixture= 100.000000
V_fixture= 2.400000
V_fixture_min= 2.000000
V_fixture_max= 2.700000
|time   V(typ)   V(min)   V(max)
0s        525.2mV    870.3mV    387.4mV
1.001ns   531.5mV    869.3mV    420.2mV
1.301ns   567.9mV    868mV      1.001V
1.502ns   596.7mV    867.3mV    1.561V
1.902ns   1.142V     936.6mV    2.282V
2.503ns   2.086V     1.12V      2.57V
3.303ns   2.322V     1.631V     2.659V
4.204ns   2.368V     1.933V     2.687V
6.306ns   2.396V     1.991V     2.697V
49.85ns   2.4V       2V         2.7V
[Rising Waveform]
R_fixture= 100.000000
V_fixture= 0.0
V_fixture_min= 0.0
V_fixture_max= 0.0
|time   V(typ)   V(min)   V(max)
0s        4.912nV    72.82nV    3.774nV
6.507ns   451.8uV    -275.8uV   76.78mV
11.51ns   69.92mV    -187.2uV   858.8mV
17.02ns   286.2mV    1.384mV    1.91V
24.52ns   864.2mV    25.62mV    2.181V
36.04ns   1.596V     124.6mV    2.238V
55.56ns   1.793V     453.1mV    2.249V
87.59ns   1.821V     984.1mV    2.249V
108.6ns   1.822V     1.138V     2.249V
249.2ns   1.822V     1.223V     2.249V
[Falling Waveform]
R_fixture= 100.000000
V_fixture= 2.400000
V_fixture_min= 2.000000
V_fixture_max= 2.700000
|time   V(typ)   V(min)   V(max)
0s        2.4V       2V         2.7V
10.01ns   2.397V     2V         2.575V
15.02ns   2.384V     2V         1.692V
20.52ns   2.146V     1.997V     696mV
29.53ns   1.357V     1.983V     450.9mV
37.04ns   798.7mV    1.943V     418.4mV
50.55ns   603.9mV    1.72V      398mV
76.58ns   543.9mV    1.148V     388.2mV
101.1ns   528mV      962.8mV    387.4mV
249.2ns   525.2mV    870.3mV    387.4mV
[Falling Waveform]
R_fixture= 100.000000
V_fixture= 0.0
V_fixture_min= 0.0
V_fixture_max= 0.0
|time   V(typ)   V(min)   V(max)
0s        1.822V     1.223V     2.249V
800.8ps   1.792V     1.218V     2.126V
1.101ns   1.605V     1.153V     1.646V
1.301ns   1.352V     1.054V     1.362V
1.502ns   1.117V     923.6mV    1.19V
2.503ns   542mV      482.9mV    367.6mV
3.203ns   237.1mV    261.9mV    133mV
3.904ns   92.92mV    115.8mV    47.56mV
7.107ns   1.477mV    2.953mV    347.4uV
49.85ns   4.912nV    72.82nV    3.774nV
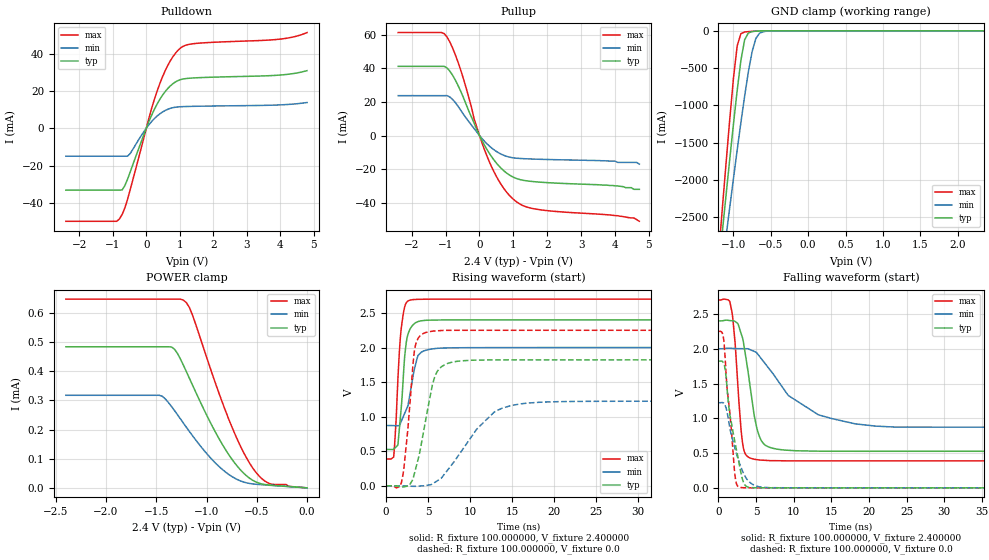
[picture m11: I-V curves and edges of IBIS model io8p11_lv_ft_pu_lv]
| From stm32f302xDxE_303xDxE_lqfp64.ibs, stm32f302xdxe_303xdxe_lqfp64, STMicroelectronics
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|   Model io8p11_lv_ft_pu_lv
[Model]  io8p11_lv_ft_pu_lv
Model_type I/O
Polarity   Non-Inverting
Enable   Active-Low
Vinl =   0.720000V
Vinh =   1.680000V
Vmeas =  1.200000V
Cref =   50.000000pF
Rref =   100.000000M
Vref =   0.0V
C_comp   5.024800pF   4.846300pF   5.260300pF
[Temperature Range]   25.000000   0.125000k   -40.000000
[Pullup Reference]   2.400000V   2.000000V   2.700000V
[Pulldown Reference]   0.0V   0.0V   0.0V
[POWER Clamp Reference]   2.400000V   2.000000V   2.700000V
[GND Clamp Reference]   0.0V   0.0V   0.0V
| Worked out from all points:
|   slope of the pulldown table from 0 to 0.36 V, typ, clamps not added: 25.5 ohm
|   slope of the pullup table from 0 to 0.36 V, typ, clamps not added: 28.4 ohm
|   GND clamp passes 1 mA (typ) near -0.60 V on its own axis
|   rising waveform, R_fixture 100.000000, V_fixture 2.400000: 20-80 % time 720ps typ, 1.17ns min, 631ps max; typ from 0.527 V to 2.4 V
|   rising waveform, R_fixture 100.000000, V_fixture 0.0: 20-80 % time 1.74ns typ, 4.7ns min, 954ps max; typ from 0.001 V to 1.82 V
|   falling waveform, R_fixture 100.000000, V_fixture 2.400000: 20-80 % time 1.6ns typ, 6.31ns min, 915ps max; typ from 2.4 V to 0.527 V
|   falling waveform, R_fixture 100.000000, V_fixture 0.0: 20-80 % time 1.59ns typ, 1.86ns min, 1.06ns max; typ from 1.82 V to 0.001 V
[Pulldown]
|Voltage   I(typ)   I(min)   I(max)
-2.4V     -33.16mA   -14.98mA   -49.86mA
-880mV    -33.16mA   -14.98mA   -49.86mA
-800mV    -33.16mA   -14.98mA   -48.55mA
-640mV    -30.75mA   -14.98mA   -42.77mA
-480mV    -23.43mA   -13.57mA   -32.92mA
80mV      3.651mA    1.905mA    5.506mA
400mV     15.37mA    7.665mA    23.73mA
720mV     22.75mA    10.69mA    36.23mA
1.04V     26.18mA    11.57mA    43.27mA
1.52V     27.09mA    11.81mA    45.55mA
4V        28.55mA    12.55mA    47.81mA
4.8V      30.9mA     13.81mA    51.31mA
[Pullup]
|Voltage   I(typ)   I(min)   I(max)
-2.4V     41.12mA    23.71mA    61.2mA
-1.12V    41.12mA    23.71mA    61.2mA
-960mV    40.18mA    23.71mA    58.57mA
-800mV    36.02mA    21.56mA    52.31mA
-560mV    26.55mA    15.19mA    39.22mA
-160mV    7.425mA    4.163mA    10.02mA
240mV     -8.976mA   -5.327mA   -13.21mA
640mV     -19.5mA    -11.08mA   -29.16mA
1.04V     -25.15mA   -13.38mA   -38.61mA
1.68V     -27.56mA   -14.07mA   -43.81mA
4.08V     -30mA      -16mA      -47.7mA
4.72V     -32mA      -17mA      -51mA
[GND_clamp]
|Voltage   I(typ)   I(min)   I(max)
-2.4V     -9.914A    -9.862A    -9.419A
-1.2V     -3.21A     -3.567A    -3.02A
-1.15V    -2.709A    -3.165A    -2.399A
-1.1V     -2.213A    -2.766A    -1.788A
-1.05V    -1.726A    -2.371A    -1.195A
-950mV    -800.5mA   -1.599A    -202.1mA
-900mV    -394.9mA   -1.228A    -38.17mA
-850mV    -120.2mA   -874.5mA   -15.91mA
-750mV    -9.807mA   -279.4mA   -7.273mA
-700mV    -4.736mA   -102mA     -4.51mA
-600mV    -1.032mA   -11.09mA   -922.6uA
2.35V     0A         0A         0A
[POWER_clamp]
|Voltage   I(typ)   I(min)   I(max)
-2.4V     483.6uA    317.4uA    647uA
-1.47V    483.6uA    317.4uA    647uA
-1.32V    475.8uA    265.5uA    647uA
-1.23V    420.2uA    221.9uA    643.4uA
-1.17V    375.2uA    193uA      618uA
-1.14V    352.5uA    178.9uA    592.4uA
-840mV    147.3uA    62.31uA    290.1uA
-690mV    72.45uA    27.83uA    163.1uA
-540mV    25.83uA    13.54uA    67.87uA
-450mV    13.39uA    10.74uA    31.49uA
-360mV    9.215uA    8.523uA    13uA
0V        0A         0A         0A
[Ramp]
| variable   typ   min   max
dV/dt_r  1.09263/1.73903n   0.73347/4.69935n   1.34920/0.94942n
dV/dt_f  1.12408/1.59636n   0.67645/6.30410n   1.38686/0.91151n
R_load = 100.000000
[Rising Waveform]
R_fixture= 100.000000
V_fixture= 2.400000
V_fixture_min= 2.000000
V_fixture_max= 2.700000
|time   V(typ)   V(min)   V(max)
0s        526.5mV    872.5mV    388.6mV
900.9ps   532.5mV    871.5mV    418.2mV
1.401ns   593.2mV    869.9mV    1.547V
1.602ns   862.2mV    877.5mV    1.994V
1.902ns   1.289V     962.4mV    2.372V
2.202ns   1.864V     1.047V     2.584V
2.703ns   2.227V     1.231V     2.679V
3.804ns   2.375V     1.886V     2.697V
5.305ns   2.396V     1.977V     2.699V
49.85ns   2.4V       2V         2.7V
[Rising Waveform]
R_fixture= 100.000000
V_fixture= 0.0
V_fixture_min= 0.0
V_fixture_max= 0.0
|time   V(typ)   V(min)   V(max)
0s        1.029mV    1.343mV    916.4uV
1.802ns   -17.88mV   325.5uV    39.95mV
2.503ns   -3.637mV   -2.736mV   715.2mV
3.403ns   194.4mV    -6.859mV   1.978V
4.605ns   880.3mV    3.174mV    2.212V
5.606ns   1.5V       36.28mV    2.238V
6.607ns   1.723V     116.4mV    2.246V
10.81ns   1.818V     821.8mV    2.249V
14.91ns   1.822V     1.162V     2.25V
49.85ns   1.822V     1.224V     2.25V
[Falling Waveform]
R_fixture= 100.000000
V_fixture= 2.400000
V_fixture_min= 2.000000
V_fixture_max= 2.700000
|time   V(typ)   V(min)   V(max)
0s        2.4V       2V         2.7V
1.301ns   2.408V     2.007V     2.702V
1.802ns   2.402V     2.006V     2.521V
3.103ns   2.186V     2.001V     728.5mV
4.204ns   1.456V     1.986V     430mV
5.606ns   698.1mV    1.868V     400.1mV
7.808ns   556.8mV    1.553V     391mV
13.21ns   528.1mV    1.055V     388.6mV
18.22ns   526.7mV    919.9mV    388.6mV
49.85ns   526.5mV    872.5mV    388.6mV
[Falling Waveform]
R_fixture= 100.000000
V_fixture= 0.0
V_fixture_min= 0.0
V_fixture_max= 0.0
|time   V(typ)   V(min)   V(max)
0s        1.822V     1.224V     2.25V
700.7ps   1.792V     1.218V     2.129V
1.101ns   1.487V     1.11V      1.482V
1.502ns   1.055V     862.2mV    1.084V
2.102ns   703mV      603.7mV    275mV
2.302ns   593.3mV    523.5mV    93.3mV
2.703ns   371.1mV    383.3mV    13.31mV
3.403ns   59.48mV    194mV      2.562mV
4.505ns   3.725mV    52.54mV    1.494mV
49.85ns   1.029mV    1.343mV    916.4uV
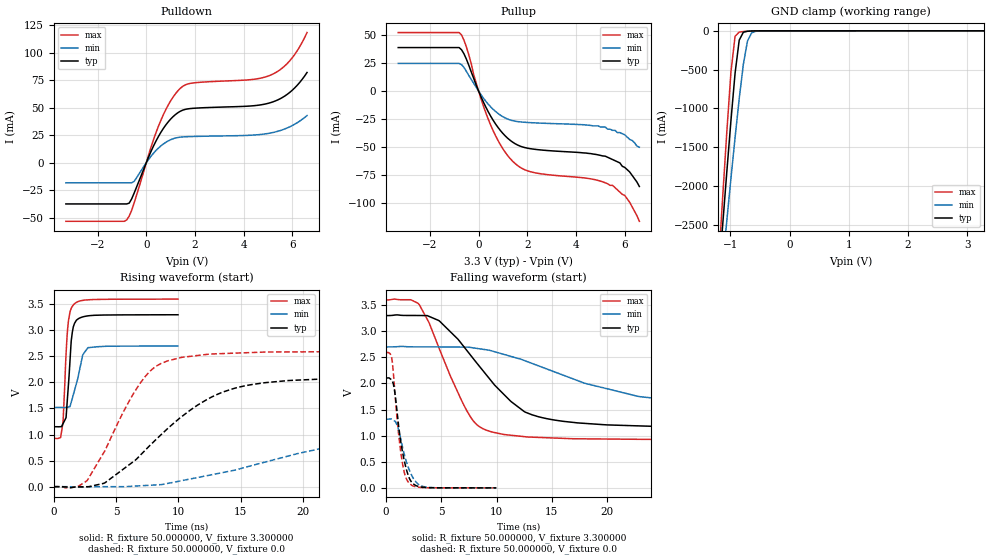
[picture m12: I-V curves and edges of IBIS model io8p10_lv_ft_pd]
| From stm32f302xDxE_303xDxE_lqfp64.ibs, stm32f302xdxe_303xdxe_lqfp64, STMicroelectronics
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|   Model io8p10_lv_ft_pd
[Model]  io8p10_lv_ft_pd
Model_type I/O
Polarity   Non-Inverting
Enable   Active-Low
Vinl =   0.990000V
Vinh =   2.310000V
Vmeas =  1.650000V
Cref =   50.000000pF
Rref =   100.000000M
Vref =   0.0V
C_comp   5.028100pF   4.857200pF   5.254400pF
[Temperature Range]   25.000000   0.125000k   -40.000000
[Pullup Reference]   3.300000V   2.700000V   3.600000V
[Pulldown Reference]   0.0V   0.0V   0.0V
[POWER Clamp Reference]   3.300000V   2.700000V   3.600000V
[GND Clamp Reference]   0.0V   0.0V   0.0V
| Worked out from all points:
|   slope of the pulldown table from 0 to 0.495 V, typ, clamps not added: 20.9 ohm
|   slope of the pullup table from 0 to 0.495 V, typ, clamps not added: 22.2 ohm
|   GND clamp passes 1 mA (typ) near -0.59 V on its own axis
|   rising waveform, R_fixture 50.000000, V_fixture 3.300000: 20-80 % time 376ps typ, 706ps min, 340ps max; typ from 1.15 V to 3.3 V
|   rising waveform, R_fixture 50.000000, V_fixture 0.0: 20-80 % time 6.33ns typ, 15ns min, 3.53ns max; typ from 0 V to 2.1 V
|   falling waveform, R_fixture 50.000000, V_fixture 3.300000: 20-80 % time 5.37ns typ, 10.5ns min, 3.28ns max; typ from 3.3 V to 1.15 V
|   falling waveform, R_fixture 50.000000, V_fixture 0.0: 20-80 % time 882ps typ, 1.07ns min, 739ps max; typ from 2.1 V to 0 V
[Pulldown]
|Voltage   I(typ)   I(min)   I(max)
-3.3V     -37.45mA   -18.2mA    -53.24mA
-800mV    -37.45mA   -18.2mA    -51.9mA
-700mV    -36.7mA    -18.2mA    -48.48mA
-500mV    -27.71mA   -17.01mA   -36.66mA
200mV     10.57mA    6.084mA    14.57mA
500mV     23.91mA    13.38mA    33.24mA
900mV     37.17mA    19.88mA    52.48mA
1.3V      45.55mA    23.01mA    65.5mA
1.8V      49.29mA    23.83mA    72.18mA
5.1V      54.68mA    27.07mA    79.72mA
5.9V      64.2mA     32.82mA    93.01mA
6.6V      82.13mA    42.97mA    118.5mA
[Pullup]
|Voltage   I(typ)   I(min)   I(max)
-3.3V     38.72mA    24.59mA    52.09mA
-800mV    38.72mA    24.59mA    52.09mA
-500mV    28.38mA    17.49mA    39.2mA
0V        0A         0A         0A
500mV     -22.5mA    -14.16mA   -30.52mA
900mV     -35.28mA   -21.55mA   -48mA
1.4V      -45.54mA   -26.4mA    -62.54mA
2.2V      -51.57mA   -28.22mA   -72.25mA
4.9V      -56.8mA    -31mA      -79.6mA
5.5V      -61mA      -35mA      -84mA
6V        -68mA      -39mA      -93mA
6.6V      -85mA      -50mA      -116mA
[GND_clamp]
|Voltage   I(typ)   I(min)   I(max)
-3.3V     -9.706A    -9.438A    -9.292A
-1.2V     -3.211A    -3.571A    -3.02A
-1.13V    -2.511A    -3.008A    -2.153A
-1.06V    -1.824A    -2.453A    -1.311A
-990mV    -1.16A     -1.907A    -534mA
-920mV    -548mA     -1.377A    -70.1mA
-850mV    -120.5mA   -875.9mA   -15.92mA
-780mV    -17.67mA   -430.9mA   -9.208mA
-710mV    -5.454mA   -130.8mA   -5.036mA
-640mV    -2.091mA   -25.66mA   -2.018mA
-570mV    -553.8uA   -6.304mA   -449uA
3.28V     83.63uA    63.63uA    93.37uA
[POWER_clamp]
|Voltage   I(typ)   I(min)   I(max)
-3.28V    0A         0A         0A
0V        0A         0A         0A
[Ramp]
| variable   typ   min   max
dV/dt_r  1.26150/6.31831n   0.77880/14.97878n   1.55376/3.52486n
dV/dt_f  1.28928/5.36712n   0.69972/10.59668n   1.60432/3.27898n
R_load = 50.000000
[Rising Waveform]
R_fixture= 50.000000
V_fixture= 3.300000
V_fixture_min= 2.700000
V_fixture_max= 3.600000
|time   V(typ)   V(min)   V(max)
0s        1.15V      1.521V     925.1mV
540.5ps   1.151V     1.52V      942.9mV
740.7ps   1.209V     1.519V     1.244V
981ps     1.323V     1.521V     2.534V
1.181ns   1.983V     1.528V     3.191V
1.401ns   2.807V     1.623V     3.424V
1.582ns   3.078V     1.779V     3.491V
2.322ns   3.258V     2.529V     3.574V
2.743ns   3.278V     2.667V     3.585V
9.97ns    3.299V     2.699V     3.599V
[Rising Waveform]
R_fixture= 50.000000
V_fixture= 0.0
V_fixture_min= 0.0
V_fixture_max= 0.0
|time   V(typ)   V(min)   V(max)
0s        -25.01uV   -17.46uV   -16.46uV
2.703ns   -1.003mV   -4.964mV   126.3mV
4.104ns   73.78mV    -622.2uV   691.1mV
7.307ns   691.9mV    21.62mV    2.105V
8.509ns   973.5mV    38.09mV    2.351V
10.21ns   1.334V     112.4mV    2.478V
13.61ns   1.819V     273.3mV    2.554V
18.82ns   2.036V     587.6mV    2.586V
30.33ns   2.1V       1.11V      2.59V
49.85ns   2.103V     1.315V     2.59V
[Falling Waveform]
R_fixture= 50.000000
V_fixture= 3.300000
V_fixture_min= 2.700000
V_fixture_max= 3.600000
|time   V(typ)   V(min)   V(max)
0s        3.299V     2.699V     3.599V
3.003ns   3.3V       2.699V     3.506V
4.805ns   3.199V     2.698V     2.669V
7.307ns   2.631V     2.694V     1.476V
8.308ns   2.364V     2.667V     1.193V
9.61ns    2.023V     2.619V     1.068V
12.61ns   1.448V     2.43V      978.1mV
17.32ns   1.244V     2.055V     939.7mV
27.63ns   1.167V     1.643V     925.9mV
49.85ns   1.15V      1.521V     925.1mV
[Falling Waveform]
R_fixture= 50.000000
V_fixture= 0.0
V_fixture_min= 0.0
V_fixture_max= 0.0
|time   V(typ)   V(min)   V(max)
0s        2.103V     1.315V     2.59V
500.5ps   2.068V     1.314V     2.488V
740.7ps   1.889V     1.282V     1.97V
1.001ns   1.433V     1.193V     1.297V
1.321ns   888.4mV    932.5mV    691.6mV
1.662ns   500mV      627.3mV    278.8mV
2.042ns   214.5mV    371.5mV    99.19mV
2.583ns   58.09mV    142.4mV    25.94mV
3.363ns   10.49mV    25.4mV     3.18mV
9.97ns    -25.01uV   -17.46uV   -16.46uV
